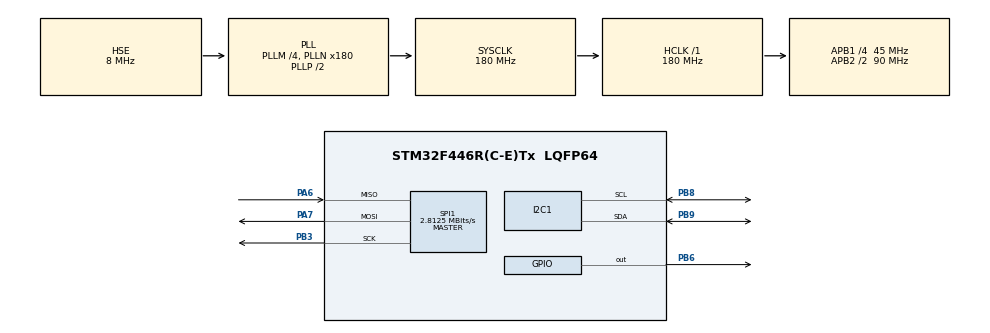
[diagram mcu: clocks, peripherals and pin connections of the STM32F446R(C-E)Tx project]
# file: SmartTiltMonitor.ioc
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Mcu.Family=STM32F4
Mcu.Name=STM32F446R(C-E)Tx
Mcu.Package=LQFP64
NVIC.PriorityGroup=NVIC_PRIORITYGROUP_4
PA6.Mode=Full_Duplex_Master
PA6.Signal=SPI1_MISO
PA7.Mode=Full_Duplex_Master
PA7.Signal=SPI1_MOSI
PB3.Mode=Full_Duplex_Master
PB3.Signal=SPI1_SCK
PB6.Signal=GPIO_Output
PB8.GPIO_Pu=GPIO_PULLUP
PB8.Mode=I2C
PB8.Signal=I2C1_SCL
PB9.GPIO_Pu=GPIO_PULLUP
PB9.Mode=I2C
PB9.Signal=I2C1_SDA
PH0-OSC_IN.Mode=HSE-External-Oscillator
PH0-OSC_IN.Signal=RCC_OSC_IN
PH1-OSC_OUT.Mode=HSE-External-Oscillator
PH1-OSC_OUT.Signal=RCC_OSC_OUT
ProjectManager.HeapSize=0x200
ProjectManager.StackSize=0x400
ProjectManager.TargetToolchain=STM32CubeIDE
RCC.AHBFreq_Value=180000000
RCC.APB1CLKDivider=RCC_HCLK_DIV4
RCC.APB1Freq_Value=45000000
RCC.APB1TimFreq_Value=90000000
RCC.APB2CLKDivider=RCC_HCLK_DIV2
RCC.APB2Freq_Value=90000000
RCC.APB2TimFreq_Value=180000000
RCC.CortexFreq_Value=180000000
RCC.HCLKFreq_Value=180000000
RCC.HSE_VALUE=8000000
RCC.PLLM=4
RCC.PLLN=180
RCC.PLLSourceVirtual=RCC_PLLSOURCE_HSE
RCC.SYSCLKFreq_VALUE=180000000
RCC.SYSCLKSource=RCC_SYSCLKSOURCE_PLLCLK
RCC.USBFreq_Value=180000000
RCC.VCOOutputFreq_Value=360000000
SPI1.BaudRatePrescaler=SPI_BAUDRATEPRESCALER_32
SPI1.CLKPhase=SPI_PHASE_2EDGE
SPI1.CLKPolarity=SPI_POLARITY_HIGH
SPI1.CalculateBaudRate=2.8125 MBits/s
SPI1.Direction=SPI_DIRECTION_2LINES
SPI1.Mode=SPI_MODE_MASTER
SPI1.VirtualType=VM_MASTER
board=custom

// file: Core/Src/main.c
/* USER CODE BEGIN Header */
/**
  ******************************************************************************
  * @file           : main.c
  * @brief          : Main program body
  ******************************************************************************
  * @attention
  *
  * Copyright (c) 2024 STMicroelectronics.
  * All rights reserved.
  *
  * This software is licensed under terms that can be found in the LICENSE file
  * in the root directory of this software component.
  * If no LICENSE file comes with this software, it is provided AS-IS.
  *
  ******************************************************************************
  */
/* USER CODE END Header */
#include <APIadxl.h>
#include <APIlcd.h>
#include <MEFtilt.h>
#include "main.h"
#include <stdio.h>

I2C_HandleTypeDef hi2c1;
SPI_HandleTypeDef hspi1;

void SystemClock_Config(void);
static void MX_GPIO_Init(void);
static void MX_SPI1_Init(void);
static void MX_I2C1_Init(void);

int main(void)
{

  /* MCU Configuration--------------------------------------------------------*/

  /* Reset of all peripherals, Initializes the Flash interface and the Systick. */
  HAL_Init();

  /* Configure the system clock */
  SystemClock_Config();

  /* Initialize all configured peripherals */
  MX_GPIO_Init();
  MX_SPI1_Init();
  MX_I2C1_Init();
  /* USER CODE BEGIN 2 */

  APILCD_init();
  ADXL345_Init();

  /* USER CODE END 2 */

  /* Infinite loop */
  while (1)
  {
    /* USER CODE END WHILE */

    /* USER CODE BEGIN 3 */

	  mefTiltRun();

  }
  /* USER CODE END 3 */
}

void SystemClock_Config(void)
{
  RCC_OscInitTypeDef RCC_OscInitStruct = {0};
  RCC_ClkInitTypeDef RCC_ClkInitStruct = {0};

  /** Configure the main internal regulator output voltage
  */
  __HAL_RCC_PWR_CLK_ENABLE();
  __HAL_PWR_VOLTAGESCALING_CONFIG(PWR_REGULATOR_VOLTAGE_SCALE1);

  /** Initializes the RCC Oscillators according to the specified parameters
  * in the RCC_OscInitTypeDef structure.
  */
  RCC_OscInitStruct.OscillatorType = RCC_OSCILLATORTYPE_HSE;
  RCC_OscInitStruct.HSEState = RCC_HSE_ON;
  RCC_OscInitStruct.PLL.PLLState = RCC_PLL_ON;
  RCC_OscInitStruct.PLL.PLLSource = RCC_PLLSOURCE_HSE;
  RCC_OscInitStruct.PLL.PLLM = 4;
  RCC_OscInitStruct.PLL.PLLN = 180;
  RCC_OscInitStruct.PLL.PLLP = RCC_PLLP_DIV2;
  RCC_OscInitStruct.PLL.PLLQ = 2;
  RCC_OscInitStruct.PLL.PLLR = 2;
  if (HAL_RCC_OscConfig(&RCC_OscInitStruct) != HAL_OK)
  {
    Error_Handler();
  }

  /** Activate the Over-Drive mode
  */
  if (HAL_PWREx_EnableOverDrive() != HAL_OK)
  {
    Error_Handler();
  }

  /** Initializes the CPU, AHB and APB buses clocks
  */
  RCC_ClkInitStruct.ClockType = RCC_CLOCKTYPE_HCLK|RCC_CLOCKTYPE_SYSCLK
                              |RCC_CLOCKTYPE_PCLK1|RCC_CLOCKTYPE_PCLK2;
  RCC_ClkInitStruct.SYSCLKSource = RCC_SYSCLKSOURCE_PLLCLK;
  RCC_ClkInitStruct.AHBCLKDivider = RCC_SYSCLK_DIV1;
  RCC_ClkInitStruct.APB1CLKDivider = RCC_HCLK_DIV4;
  RCC_ClkInitStruct.APB2CLKDivider = RCC_HCLK_DIV2;

  if (HAL_RCC_ClockConfig(&RCC_ClkInitStruct, FLASH_LATENCY_5) != HAL_OK)
  {
    Error_Handler();
  }
}

static void MX_I2C1_Init(void)
{

  hi2c1.Instance = I2C1;
  hi2c1.Init.ClockSpeed = 100000;
  hi2c1.Init.DutyCycle = I2C_DUTYCYCLE_2;
  hi2c1.Init.OwnAddress1 = 0;
  hi2c1.Init.AddressingMode = I2C_ADDRESSINGMODE_7BIT;
  hi2c1.Init.DualAddressMode = I2C_DUALADDRESS_DISABLE;
  hi2c1.Init.OwnAddress2 = 0;
  hi2c1.Init.GeneralCallMode = I2C_GENERALCALL_DISABLE;
  hi2c1.Init.NoStretchMode = I2C_NOSTRETCH_DISABLE;
  if (HAL_I2C_Init(&hi2c1) != HAL_OK)
  {
    Error_Handler();
  }

}

static void MX_SPI1_Init(void)
{

  /* SPI1 parameter configuration*/
  hspi1.Instance = SPI1;
  hspi1.Init.Mode = SPI_MODE_MASTER;
  hspi1.Init.Direction = SPI_DIRECTION_2LINES;
  hspi1.Init.DataSize = SPI_DATASIZE_8BIT;
  hspi1.Init.CLKPolarity = SPI_POLARITY_HIGH;
  hspi1.Init.CLKPhase = SPI_PHASE_2EDGE;
  hspi1.Init.NSS = SPI_NSS_SOFT;
  hspi1.Init.BaudRatePrescaler = SPI_BAUDRATEPRESCALER_32;
  hspi1.Init.FirstBit = SPI_FIRSTBIT_MSB;
  hspi1.Init.TIMode = SPI_TIMODE_DISABLE;
  hspi1.Init.CRCCalculation = SPI_CRCCALCULATION_DISABLE;
  hspi1.Init.CRCPolynomial = 10;
  if (HAL_SPI_Init(&hspi1) != HAL_OK)
  {
    Error_Handler();
  }

}

static void MX_GPIO_Init(void)
{
  GPIO_InitTypeDef GPIO_InitStruct = {0};

  /* GPIO Ports Clock Enable */
  __HAL_RCC_GPIOH_CLK_ENABLE();
  __HAL_RCC_GPIOA_CLK_ENABLE();
  __HAL_RCC_GPIOB_CLK_ENABLE();
  __HAL_RCC_GPIOC_CLK_ENABLE();

  /*Configure GPIO pin Output Level */
  HAL_GPIO_WritePin(GPIOB, GPIO_PIN_6, GPIO_PIN_SET);
  HAL_GPIO_WritePin(LD2_GPIO_Port, LD2_Pin, GPIO_PIN_RESET);

  /*Configure GPIO pin : PB6 */
  GPIO_InitStruct.Pin = GPIO_PIN_6;
  GPIO_InitStruct.Mode = GPIO_MODE_OUTPUT_PP;
  GPIO_InitStruct.Pull = GPIO_NOPULL;
  GPIO_InitStruct.Speed = GPIO_SPEED_FREQ_LOW;
  HAL_GPIO_Init(GPIOB, &GPIO_InitStruct);

  /*Configure GPIO pin : PB13 */
  GPIO_InitStruct.Pin = GPIO_PIN_13;
  GPIO_InitStruct.Mode = GPIO_MODE_INPUT;
  GPIO_InitStruct.Pull = GPIO_NOPULL;
  HAL_GPIO_Init(GPIOC, &GPIO_InitStruct);

  /*Configure GPIO pin : LD2_Pin */
    GPIO_InitStruct.Pin = LD2_Pin;
    GPIO_InitStruct.Mode = GPIO_MODE_OUTPUT_PP;
    GPIO_InitStruct.Pull = GPIO_NOPULL;
    GPIO_InitStruct.Speed = GPIO_SPEED_FREQ_LOW;
    HAL_GPIO_Init(LD2_GPIO_Port, &GPIO_InitStruct);

}

void Error_Handler(void)
{
  __disable_irq();
  while (1)
  {
  }
}
